VERSION 5.8 ;
BUSBITCHARS "[]" ;
DIVIDERCHAR "/" ;
UNITS
    DATABASE MICRONS 1000 ;
END UNITS

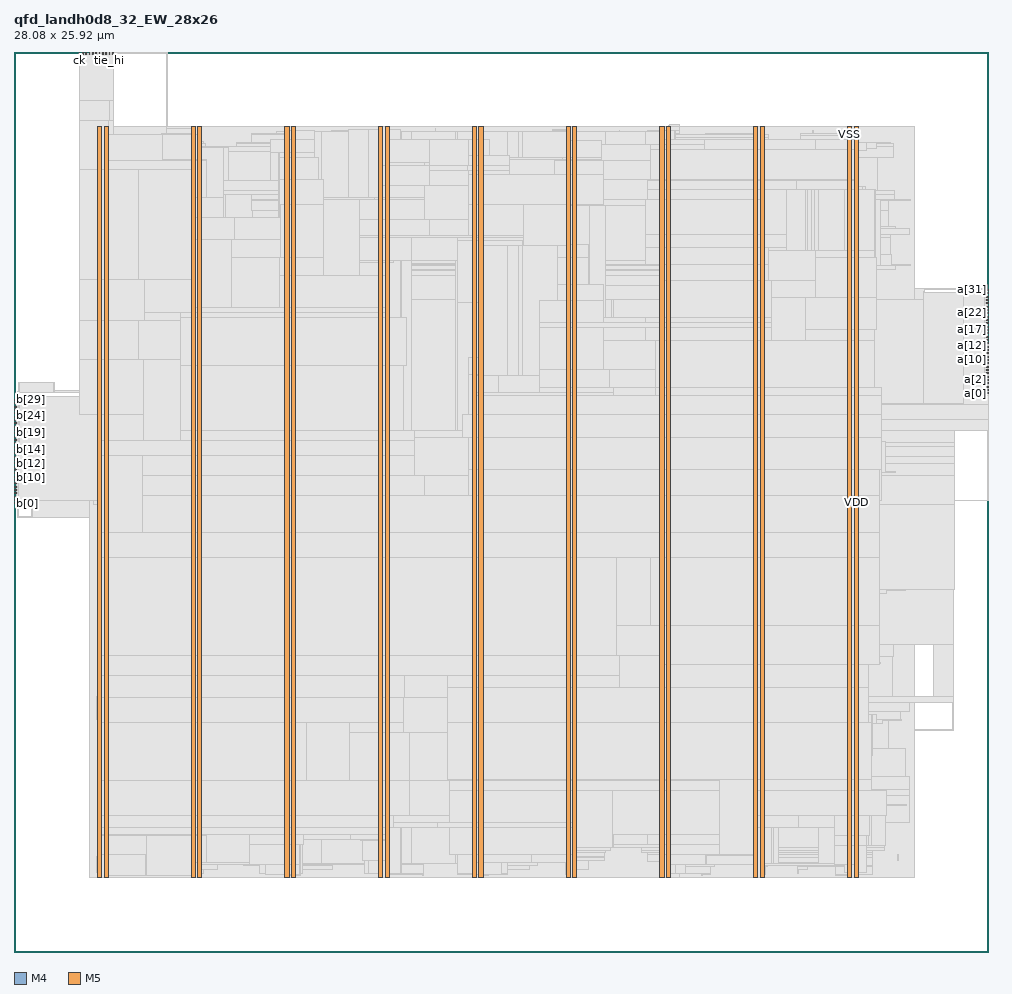
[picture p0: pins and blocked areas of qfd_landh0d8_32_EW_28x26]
MACRO qfd_landh0d8_32_EW_28x26
  FOREIGN qfd_landh0d8_32_EW_28x26 0 0 ;
  CLASS BLOCK ;
  SIZE 28.08 BY 25.92 ;
  PIN a[0]
    DIRECTION INPUT ;
    USE SIGNAL ;
    PORT
      LAYER M4 ;
        RECT  27.996 16.08 28.08 16.104 ;
    END
  END a[0]
  PIN a[10]
    DIRECTION INPUT ;
    USE SIGNAL ;
    PORT
      LAYER M4 ;
        RECT  27.996 17.04 28.08 17.064 ;
    END
  END a[10]
  PIN a[11]
    DIRECTION INPUT ;
    USE SIGNAL ;
    PORT
      LAYER M4 ;
        RECT  27.996 17.136 28.08 17.16 ;
    END
  END a[11]
  PIN a[12]
    DIRECTION INPUT ;
    USE SIGNAL ;
    PORT
      LAYER M4 ;
        RECT  27.996 17.232 28.08 17.256 ;
    END
  END a[12]
  PIN a[13]
    DIRECTION INPUT ;
    USE SIGNAL ;
    PORT
      LAYER M4 ;
        RECT  27.996 17.328 28.08 17.352 ;
    END
  END a[13]
  PIN a[14]
    DIRECTION INPUT ;
    USE SIGNAL ;
    PORT
      LAYER M4 ;
        RECT  27.996 17.424 28.08 17.448 ;
    END
  END a[14]
  PIN a[15]
    DIRECTION INPUT ;
    USE SIGNAL ;
    PORT
      LAYER M4 ;
        RECT  27.996 17.52 28.08 17.544 ;
    END
  END a[15]
  PIN a[16]
    DIRECTION INPUT ;
    USE SIGNAL ;
    PORT
      LAYER M4 ;
        RECT  27.996 17.616 28.08 17.64 ;
    END
  END a[16]
  PIN a[17]
    DIRECTION INPUT ;
    USE SIGNAL ;
    PORT
      LAYER M4 ;
        RECT  27.996 17.712 28.08 17.736 ;
    END
  END a[17]
  PIN a[18]
    DIRECTION INPUT ;
    USE SIGNAL ;
    PORT
      LAYER M4 ;
        RECT  27.996 17.808 28.08 17.832 ;
    END
  END a[18]
  PIN a[19]
    DIRECTION INPUT ;
    USE SIGNAL ;
    PORT
      LAYER M4 ;
        RECT  27.996 17.904 28.08 17.928 ;
    END
  END a[19]
  PIN a[1]
    DIRECTION INPUT ;
    USE SIGNAL ;
    PORT
      LAYER M4 ;
        RECT  27.996 16.176 28.08 16.2 ;
    END
  END a[1]
  PIN a[20]
    DIRECTION INPUT ;
    USE SIGNAL ;
    PORT
      LAYER M4 ;
        RECT  27.996 18 28.08 18.024 ;
    END
  END a[20]
  PIN a[21]
    DIRECTION INPUT ;
    USE SIGNAL ;
    PORT
      LAYER M4 ;
        RECT  27.996 18.096 28.08 18.12 ;
    END
  END a[21]
  PIN a[22]
    DIRECTION INPUT ;
    USE SIGNAL ;
    PORT
      LAYER M4 ;
        RECT  27.996 18.192 28.08 18.216 ;
    END
  END a[22]
  PIN a[23]
    DIRECTION INPUT ;
    USE SIGNAL ;
    PORT
      LAYER M4 ;
        RECT  27.996 18.288 28.08 18.312 ;
    END
  END a[23]
  PIN a[24]
    DIRECTION INPUT ;
    USE SIGNAL ;
    PORT
      LAYER M4 ;
        RECT  27.996 18.384 28.08 18.408 ;
    END
  END a[24]
  PIN a[25]
    DIRECTION INPUT ;
    USE SIGNAL ;
    PORT
      LAYER M4 ;
        RECT  27.996 18.48 28.08 18.504 ;
    END
  END a[25]
  PIN a[26]
    DIRECTION INPUT ;
    USE SIGNAL ;
    PORT
      LAYER M4 ;
        RECT  27.996 18.576 28.08 18.6 ;
    END
  END a[26]
  PIN a[27]
    DIRECTION INPUT ;
    USE SIGNAL ;
    PORT
      LAYER M4 ;
        RECT  27.996 18.672 28.08 18.696 ;
    END
  END a[27]
  PIN a[28]
    DIRECTION INPUT ;
    USE SIGNAL ;
    PORT
      LAYER M4 ;
        RECT  27.996 18.768 28.08 18.792 ;
    END
  END a[28]
  PIN a[29]
    DIRECTION INPUT ;
    USE SIGNAL ;
    PORT
      LAYER M4 ;
        RECT  27.996 18.864 28.08 18.888 ;
    END
  END a[29]
  PIN a[2]
    DIRECTION INPUT ;
    USE SIGNAL ;
    PORT
      LAYER M4 ;
        RECT  27.996 16.272 28.08 16.296 ;
    END
  END a[2]
  PIN a[30]
    DIRECTION INPUT ;
    USE SIGNAL ;
    PORT
      LAYER M4 ;
        RECT  27.996 18.96 28.08 18.984 ;
    END
  END a[30]
  PIN a[31]
    DIRECTION INPUT ;
    USE SIGNAL ;
    PORT
      LAYER M4 ;
        RECT  27.996 19.056 28.08 19.08 ;
    END
  END a[31]
  PIN a[3]
    DIRECTION INPUT ;
    USE SIGNAL ;
    PORT
      LAYER M4 ;
        RECT  27.996 16.368 28.08 16.392 ;
    END
  END a[3]
  PIN a[4]
    DIRECTION INPUT ;
    USE SIGNAL ;
    PORT
      LAYER M4 ;
        RECT  27.996 16.464 28.08 16.488 ;
    END
  END a[4]
  PIN a[5]
    DIRECTION INPUT ;
    USE SIGNAL ;
    PORT
      LAYER M4 ;
        RECT  27.996 16.56 28.08 16.584 ;
    END
  END a[5]
  PIN a[6]
    DIRECTION INPUT ;
    USE SIGNAL ;
    PORT
      LAYER M4 ;
        RECT  27.996 16.656 28.08 16.68 ;
    END
  END a[6]
  PIN a[7]
    DIRECTION INPUT ;
    USE SIGNAL ;
    PORT
      LAYER M4 ;
        RECT  27.996 16.752 28.08 16.776 ;
    END
  END a[7]
  PIN a[8]
    DIRECTION INPUT ;
    USE SIGNAL ;
    PORT
      LAYER M4 ;
        RECT  27.996 16.848 28.08 16.872 ;
    END
  END a[8]
  PIN a[9]
    DIRECTION INPUT ;
    USE SIGNAL ;
    PORT
      LAYER M4 ;
        RECT  27.996 16.944 28.08 16.968 ;
    END
  END a[9]
  PIN b[0]
    DIRECTION OUTPUT ;
    USE SIGNAL ;
    PORT
      LAYER M4 ;
        RECT  0 12.912 0.084 12.936 ;
    END
  END b[0]
  PIN b[10]
    DIRECTION OUTPUT ;
    USE SIGNAL ;
    PORT
      LAYER M4 ;
        RECT  0 13.872 0.084 13.896 ;
    END
  END b[10]
  PIN b[11]
    DIRECTION OUTPUT ;
    USE SIGNAL ;
    PORT
      LAYER M4 ;
        RECT  0 13.968 0.084 13.992 ;
    END
  END b[11]
  PIN b[12]
    DIRECTION OUTPUT ;
    USE SIGNAL ;
    PORT
      LAYER M4 ;
        RECT  0 14.064 0.084 14.088 ;
    END
  END b[12]
  PIN b[13]
    DIRECTION OUTPUT ;
    USE SIGNAL ;
    PORT
      LAYER M4 ;
        RECT  0 14.16 0.084 14.184 ;
    END
  END b[13]
  PIN b[14]
    DIRECTION OUTPUT ;
    USE SIGNAL ;
    PORT
      LAYER M4 ;
        RECT  0 14.256 0.084 14.28 ;
    END
  END b[14]
  PIN b[15]
    DIRECTION OUTPUT ;
    USE SIGNAL ;
    PORT
      LAYER M4 ;
        RECT  0 14.352 0.084 14.376 ;
    END
  END b[15]
  PIN b[16]
    DIRECTION OUTPUT ;
    USE SIGNAL ;
    PORT
      LAYER M4 ;
        RECT  0 14.448 0.084 14.472 ;
    END
  END b[16]
  PIN b[17]
    DIRECTION OUTPUT ;
    USE SIGNAL ;
    PORT
      LAYER M4 ;
        RECT  0 14.544 0.084 14.568 ;
    END
  END b[17]
  PIN b[18]
    DIRECTION OUTPUT ;
    USE SIGNAL ;
    PORT
      LAYER M4 ;
        RECT  0 14.64 0.084 14.664 ;
    END
  END b[18]
  PIN b[19]
    DIRECTION OUTPUT ;
    USE SIGNAL ;
    PORT
      LAYER M4 ;
        RECT  0 14.736 0.084 14.76 ;
    END
  END b[19]
  PIN b[1]
    DIRECTION OUTPUT ;
    USE SIGNAL ;
    PORT
      LAYER M4 ;
        RECT  0 13.008 0.084 13.032 ;
    END
  END b[1]
  PIN b[20]
    DIRECTION OUTPUT ;
    USE SIGNAL ;
    PORT
      LAYER M4 ;
        RECT  0 14.832 0.084 14.856 ;
    END
  END b[20]
  PIN b[21]
    DIRECTION OUTPUT ;
    USE SIGNAL ;
    PORT
      LAYER M4 ;
        RECT  0 14.928 0.084 14.952 ;
    END
  END b[21]
  PIN b[22]
    DIRECTION OUTPUT ;
    USE SIGNAL ;
    PORT
      LAYER M4 ;
        RECT  0 15.024 0.084 15.048 ;
    END
  END b[22]
  PIN b[23]
    DIRECTION OUTPUT ;
    USE SIGNAL ;
    PORT
      LAYER M4 ;
        RECT  0 15.12 0.084 15.144 ;
    END
  END b[23]
  PIN b[24]
    DIRECTION OUTPUT ;
    USE SIGNAL ;
    PORT
      LAYER M4 ;
        RECT  0 15.216 0.084 15.24 ;
    END
  END b[24]
  PIN b[25]
    DIRECTION OUTPUT ;
    USE SIGNAL ;
    PORT
      LAYER M4 ;
        RECT  0 15.312 0.084 15.336 ;
    END
  END b[25]
  PIN b[26]
    DIRECTION OUTPUT ;
    USE SIGNAL ;
    PORT
      LAYER M4 ;
        RECT  0 15.408 0.084 15.432 ;
    END
  END b[26]
  PIN b[27]
    DIRECTION OUTPUT ;
    USE SIGNAL ;
    PORT
      LAYER M4 ;
        RECT  0 15.504 0.084 15.528 ;
    END
  END b[27]
  PIN b[28]
    DIRECTION OUTPUT ;
    USE SIGNAL ;
    PORT
      LAYER M4 ;
        RECT  0 15.6 0.084 15.624 ;
    END
  END b[28]
  PIN b[29]
    DIRECTION OUTPUT ;
    USE SIGNAL ;
    PORT
      LAYER M4 ;
        RECT  0 15.696 0.084 15.72 ;
    END
  END b[29]
  PIN b[2]
    DIRECTION OUTPUT ;
    USE SIGNAL ;
    PORT
      LAYER M4 ;
        RECT  0 13.104 0.084 13.128 ;
    END
  END b[2]
  PIN b[30]
    DIRECTION OUTPUT ;
    USE SIGNAL ;
    PORT
      LAYER M4 ;
        RECT  0 15.792 0.084 15.816 ;
    END
  END b[30]
  PIN b[31]
    DIRECTION OUTPUT ;
    USE SIGNAL ;
    PORT
      LAYER M4 ;
        RECT  0 15.888 0.084 15.912 ;
    END
  END b[31]
  PIN b[3]
    DIRECTION OUTPUT ;
    USE SIGNAL ;
    PORT
      LAYER M4 ;
        RECT  0 13.2 0.084 13.224 ;
    END
  END b[3]
  PIN b[4]
    DIRECTION OUTPUT ;
    USE SIGNAL ;
    PORT
      LAYER M4 ;
        RECT  0 13.296 0.084 13.32 ;
    END
  END b[4]
  PIN b[5]
    DIRECTION OUTPUT ;
    USE SIGNAL ;
    PORT
      LAYER M4 ;
        RECT  0 13.392 0.084 13.416 ;
    END
  END b[5]
  PIN b[6]
    DIRECTION OUTPUT ;
    USE SIGNAL ;
    PORT
      LAYER M4 ;
        RECT  0 13.488 0.084 13.512 ;
    END
  END b[6]
  PIN b[7]
    DIRECTION OUTPUT ;
    USE SIGNAL ;
    PORT
      LAYER M4 ;
        RECT  0 13.584 0.084 13.608 ;
    END
  END b[7]
  PIN b[8]
    DIRECTION OUTPUT ;
    USE SIGNAL ;
    PORT
      LAYER M4 ;
        RECT  0 13.68 0.084 13.704 ;
    END
  END b[8]
  PIN b[9]
    DIRECTION OUTPUT ;
    USE SIGNAL ;
    PORT
      LAYER M4 ;
        RECT  0 13.776 0.084 13.8 ;
    END
  END b[9]
  PIN ck
    DIRECTION INPUT ;
    USE SIGNAL ;
    PORT
      LAYER M5 ;
        RECT  1.872 25.836 1.896 25.92 ;
    END
  END ck
  PIN ck_s
    DIRECTION INPUT ;
    USE SIGNAL ;
    PORT
      LAYER M5 ;
        RECT  1.968 25.836 1.992 25.92 ;
    END
  END ck_s
  PIN en
    DIRECTION INPUT ;
    USE SIGNAL ;
    PORT
      LAYER M5 ;
        RECT  2.064 25.836 2.088 25.92 ;
    END
  END en
  PIN fault
    DIRECTION OUTPUT ;
    USE SIGNAL ;
    PORT
      LAYER M5 ;
        RECT  2.16 25.836 2.184 25.92 ;
    END
  END fault
  PIN k0
    DIRECTION INPUT ;
    USE SIGNAL ;
    PORT
      LAYER M5 ;
        RECT  2.256 25.836 2.28 25.92 ;
    END
  END k0
  PIN k1
    DIRECTION INPUT ;
    USE SIGNAL ;
    PORT
      LAYER M5 ;
        RECT  2.352 25.836 2.376 25.92 ;
    END
  END k1
  PIN k2
    DIRECTION INPUT ;
    USE SIGNAL ;
    PORT
      LAYER M5 ;
        RECT  2.448 25.836 2.472 25.92 ;
    END
  END k2
  PIN k3
    DIRECTION INPUT ;
    USE SIGNAL ;
    PORT
      LAYER M5 ;
        RECT  2.544 25.836 2.568 25.92 ;
    END
  END k3
  PIN rs
    DIRECTION INPUT ;
    USE SIGNAL ;
    PORT
      LAYER M5 ;
        RECT  2.64 25.836 2.664 25.92 ;
    END
  END rs
  PIN tie_hi
    DIRECTION OUTPUT ;
    USE SIGNAL ;
    PORT
      LAYER M5 ;
        RECT  2.736 25.836 2.76 25.92 ;
    END
  END tie_hi
  PIN tie_lo
    DIRECTION OUTPUT ;
    USE SIGNAL ;
    PORT
      LAYER M5 ;
        RECT  2.832 25.836 2.856 25.92 ;
    END
  END tie_lo
  PIN VDD
    DIRECTION INOUT ;
    USE POWER ;
    PORT
      LAYER M5 ;
        RECT  24.192 2.151 24.312 23.769 ;
        RECT  21.492 2.151 21.612 23.769 ;
        RECT  18.792 2.151 18.912 23.769 ;
        RECT  16.092 2.151 16.212 23.769 ;
        RECT  13.392 2.151 13.512 23.769 ;
        RECT  10.692 2.151 10.812 23.769 ;
        RECT  7.992 2.151 8.112 23.769 ;
        RECT  5.292 2.151 5.412 23.769 ;
        RECT  2.592 2.151 2.712 23.769 ;
    END
  END VDD
  PIN VSS
    DIRECTION INOUT ;
    USE GROUND ;
    PORT
      LAYER M5 ;
        RECT  24 2.137 24.12 23.783 ;
        RECT  21.3 2.137 21.42 23.783 ;
        RECT  18.6 2.137 18.72 23.783 ;
        RECT  15.9 2.137 16.02 23.783 ;
        RECT  13.2 2.137 13.32 23.783 ;
        RECT  10.5 2.137 10.62 23.783 ;
        RECT  7.8 2.137 7.92 23.783 ;
        RECT  5.1 2.137 5.22 23.783 ;
        RECT  2.4 2.137 2.52 23.783 ;
    END
  END VSS
  # OT_OBS_CLOSED layer=M5 d_um=1.536 added=76
  OBS
    LAYER RVTN ;
     RECT  2.16 2.16 25.92 2.295 ;
     RECT  2.16 2.565 25.92 2.835 ;
     RECT  2.16 3.105 25.92 3.375 ;
     RECT  2.16 3.645 25.92 3.915 ;
     RECT  2.16 4.185 25.92 4.455 ;
     RECT  2.16 4.725 25.92 4.995 ;
     RECT  2.16 5.265 25.92 5.535 ;
     RECT  2.16 5.805 25.92 6.075 ;
     RECT  2.16 6.345 25.92 6.615 ;
     RECT  2.16 6.885 25.92 7.155 ;
     RECT  2.16 7.425 25.92 7.695 ;
     RECT  2.16 7.965 25.92 8.235 ;
     RECT  2.16 8.505 25.92 8.775 ;
     RECT  2.16 9.045 25.92 9.315 ;
     RECT  2.16 9.585 25.92 9.855 ;
     RECT  2.16 10.125 25.92 10.395 ;
     RECT  2.16 10.665 25.92 10.935 ;
     RECT  2.16 11.205 25.92 11.475 ;
     RECT  2.16 11.745 25.92 12.015 ;
     RECT  2.16 12.285 25.92 12.555 ;
     RECT  2.16 12.825 25.92 13.095 ;
     RECT  2.16 13.365 25.92 13.635 ;
     RECT  2.16 13.905 25.92 14.175 ;
     RECT  2.16 14.445 25.92 14.715 ;
     RECT  2.16 14.985 25.92 15.255 ;
     RECT  2.16 15.525 25.92 15.795 ;
     RECT  2.16 16.065 25.92 16.335 ;
     RECT  2.16 16.605 25.92 16.875 ;
     RECT  2.16 17.145 25.92 17.415 ;
     RECT  2.16 17.685 25.92 17.955 ;
     RECT  2.16 18.225 25.92 18.495 ;
     RECT  2.16 18.765 25.92 19.035 ;
     RECT  2.16 19.305 25.92 19.575 ;
     RECT  2.16 19.845 25.92 20.115 ;
     RECT  2.16 20.385 25.92 20.655 ;
     RECT  2.16 20.925 25.92 21.195 ;
     RECT  2.16 21.465 25.92 21.735 ;
     RECT  2.16 22.005 25.92 22.275 ;
     RECT  2.16 22.545 25.92 22.815 ;
     RECT  2.16 23.085 25.92 23.355 ;
     RECT  2.16 23.625 25.92 23.76 ;
    LAYER RVTP ;
     RECT  2.16 2.295 25.92 2.565 ;
     RECT  2.16 2.835 25.92 3.105 ;
     RECT  2.16 3.375 25.92 3.645 ;
     RECT  2.16 3.915 25.92 4.185 ;
     RECT  2.16 4.455 25.92 4.725 ;
     RECT  2.16 4.995 25.92 5.265 ;
     RECT  2.16 5.535 25.92 5.805 ;
     RECT  2.16 6.075 25.92 6.345 ;
     RECT  2.16 6.615 25.92 6.885 ;
     RECT  2.16 7.155 25.92 7.425 ;
     RECT  2.16 7.695 25.92 7.965 ;
     RECT  2.16 8.235 25.92 8.505 ;
     RECT  2.16 8.775 25.92 9.045 ;
     RECT  2.16 9.315 25.92 9.585 ;
     RECT  2.16 9.855 25.92 10.125 ;
     RECT  2.16 10.395 25.92 10.665 ;
     RECT  2.16 10.935 25.92 11.205 ;
     RECT  2.16 11.475 25.92 11.745 ;
     RECT  2.16 12.015 25.92 12.285 ;
     RECT  2.16 12.555 25.92 12.825 ;
     RECT  2.16 13.095 25.92 13.365 ;
     RECT  2.16 13.635 25.92 13.905 ;
     RECT  2.16 14.175 25.92 14.445 ;
     RECT  2.16 14.715 25.92 14.985 ;
     RECT  2.16 15.255 25.92 15.525 ;
     RECT  2.16 15.795 25.92 16.065 ;
     RECT  2.16 16.335 25.92 16.605 ;
     RECT  2.16 16.875 25.92 17.145 ;
     RECT  2.16 17.415 25.92 17.685 ;
     RECT  2.16 17.955 25.92 18.225 ;
     RECT  2.16 18.495 25.92 18.765 ;
     RECT  2.16 19.035 25.92 19.305 ;
     RECT  2.16 19.575 25.92 19.845 ;
     RECT  2.16 20.115 25.92 20.385 ;
     RECT  2.16 20.655 25.92 20.925 ;
     RECT  2.16 21.195 25.92 21.465 ;
     RECT  2.16 21.735 25.92 22.005 ;
     RECT  2.16 22.275 25.92 22.545 ;
     RECT  2.16 22.815 25.92 23.085 ;
     RECT  2.16 23.355 25.92 23.625 ;
    LAYER M1 ;
     RECT  2.16 2.151 25.92 23.769 ;
    LAYER M2 ;
     RECT  0.103 16.11 0.139 16.128 ;
     RECT  0.103 14.652 0.347 15.012 ;
     RECT  0.103 12.528 0.499 12.546 ;
     RECT  0.499 12.528 0.535 13.086 ;
     RECT  0.139 16.11 1.175 16.398 ;
     RECT  0.535 12.528 2.16 13.662 ;
     RECT  1.175 16.11 2.16 16.164 ;
     RECT  2.16 2.151 18.859 23.769 ;
     RECT  18.859 2.151 19.175 23.814 ;
     RECT  19.175 2.151 25.92 23.769 ;
     RECT  25.92 9.36 25.943 9.378 ;
     RECT  25.92 12.528 25.979 13.428 ;
     RECT  25.92 15.03 26.231 19.098 ;
     RECT  25.92 7.2 26.519 7.218 ;
     RECT  25.979 12.996 26.555 13.428 ;
     RECT  26.231 15.03 26.771 18.288 ;
     RECT  25.92 6.39 27.059 6.408 ;
     RECT  25.92 10.44 27.095 10.458 ;
     RECT  26.771 16.11 27.383 18.288 ;
     RECT  26.771 15.03 27.419 15.318 ;
     RECT  27.383 16.11 27.455 16.398 ;
     RECT  27.383 17.226 27.455 17.514 ;
     RECT  27.419 15.03 27.491 15.048 ;
     RECT  27.455 16.38 27.527 16.398 ;
     RECT  27.383 18.27 27.527 18.288 ;
     RECT  26.231 19.08 27.995 19.098 ;
     RECT  26.555 12.996 28.067 13.014 ;
     RECT  27.455 17.496 28.067 17.514 ;
    LAYER M3 ;
     RECT  2.415 2.143 2.505 2.191 ;
     RECT  7.815 2.143 7.905 2.191 ;
     RECT  13.215 2.143 13.305 2.191 ;
     RECT  24.015 2.143 24.105 2.191 ;
     RECT  5.115 2.143 5.205 2.203 ;
     RECT  10.515 2.143 10.605 2.227 ;
     RECT  11.772 2.191 11.79 2.227 ;
     RECT  13.215 2.191 13.662 2.227 ;
     RECT  15.915 2.143 16.005 2.227 ;
     RECT  18.615 2.143 18.705 2.227 ;
     RECT  19.8 2.191 19.818 2.227 ;
     RECT  21.315 2.143 21.405 2.227 ;
     RECT  23.652 2.191 24.105 2.227 ;
     RECT  7.815 2.191 8.082 2.251 ;
     RECT  10.515 2.227 11.79 2.251 ;
     RECT  18.615 2.227 18.846 2.251 ;
     RECT  19.8 2.227 20.07 2.251 ;
     RECT  5.004 2.203 5.205 2.263 ;
     RECT  2.415 2.191 2.934 2.299 ;
     RECT  2.376 2.299 2.934 2.371 ;
     RECT  5.004 2.263 5.454 2.371 ;
     RECT  7.092 2.251 8.298 2.371 ;
     RECT  12.78 2.227 14.202 2.371 ;
     RECT  15.876 2.227 16.005 2.371 ;
     RECT  22.572 2.263 22.59 2.371 ;
     RECT  2.376 2.371 3.762 2.461 ;
     RECT  18.615 2.251 20.07 2.461 ;
     RECT  21.315 2.227 21.654 2.461 ;
     RECT  22.572 2.371 22.842 2.461 ;
     RECT  23.652 2.227 24.714 2.461 ;
     RECT  7.092 2.371 9.162 2.497 ;
     RECT  12.78 2.371 14.85 2.497 ;
     RECT  21.315 2.461 21.69 2.497 ;
     RECT  22.572 2.461 24.714 2.497 ;
     RECT  2.376 2.461 4.122 2.533 ;
     RECT  5.004 2.371 5.85 2.533 ;
     RECT  6.624 2.497 9.162 2.533 ;
     RECT  10.116 2.251 11.79 2.533 ;
     RECT  12.78 2.497 15.066 2.569 ;
     RECT  2.376 2.533 11.79 2.587 ;
     RECT  12.78 2.569 15.138 2.587 ;
     RECT  18.615 2.461 20.178 2.605 ;
     RECT  15.876 2.371 16.542 2.641 ;
     RECT  2.376 2.587 15.138 2.731 ;
     RECT  15.876 2.641 17.01 2.731 ;
     RECT  21.315 2.497 24.714 2.731 ;
     RECT  2.376 2.731 17.01 2.759 ;
     RECT  25.452 2.641 25.47 2.795 ;
     RECT  18.252 2.605 20.502 2.803 ;
     RECT  21.276 2.731 24.714 2.803 ;
     RECT  2.415 2.759 17.01 2.875 ;
     RECT  18.252 2.803 24.714 2.875 ;
     RECT  2.415 2.875 17.046 2.911 ;
     RECT  18.072 2.875 24.714 2.911 ;
     RECT  2.415 2.911 17.19 3.001 ;
     RECT  18.072 2.911 25.074 3.001 ;
     RECT  2.415 3.001 25.074 3.721 ;
     RECT  2.415 3.721 25.794 4.495 ;
     RECT  2.412 4.495 25.794 4.685 ;
     RECT  2.415 4.685 25.794 5.063 ;
     RECT  2.415 5.063 25.686 5.873 ;
     RECT  2.415 5.873 25.182 6.667 ;
     RECT  2.415 6.667 25.542 6.691 ;
     RECT  2.376 6.691 25.542 6.925 ;
     RECT  2.376 6.925 25.794 7.195 ;
     RECT  27.036 6.385 27.054 7.195 ;
     RECT  2.376 7.195 27.054 7.349 ;
     RECT  2.415 7.349 25.29 8.509 ;
     RECT  2.415 8.509 25.326 8.851 ;
     RECT  26.496 7.349 27.054 8.851 ;
     RECT  2.415 8.851 27.054 10.435 ;
     RECT  0.108 12.523 0.126 12.829 ;
     RECT  2.415 10.435 27.09 12.893 ;
     RECT  2.415 12.893 15.102 12.901 ;
     RECT  0.108 12.829 0.558 12.941 ;
     RECT  2.304 12.901 15.102 13.037 ;
     RECT  0.144 12.941 0.558 13.325 ;
     RECT  2.415 13.037 15.102 13.325 ;
     RECT  0.504 13.325 0.558 13.517 ;
     RECT  0.54 13.517 0.558 13.709 ;
     RECT  15.84 12.893 27.09 13.711 ;
     RECT  2.415 13.325 14.598 13.801 ;
     RECT  2.304 13.801 14.598 14.059 ;
     RECT  2.268 14.059 14.598 14.071 ;
     RECT  15.336 13.711 27.09 14.071 ;
     RECT  2.268 14.071 27.09 14.279 ;
     RECT  0.144 14.347 0.162 14.539 ;
     RECT  2.304 14.279 27.09 14.549 ;
     RECT  0.144 14.539 0.234 14.635 ;
     RECT  0.108 14.635 0.234 14.647 ;
     RECT  2.415 14.549 27.09 14.675 ;
     RECT  12.492 14.675 27.09 15.025 ;
     RECT  28.044 12.991 28.062 15.025 ;
     RECT  0.108 14.647 0.342 15.053 ;
     RECT  2.415 14.675 11.718 15.251 ;
     RECT  12.492 15.025 28.062 15.341 ;
     RECT  2.415 15.251 5.778 15.449 ;
     RECT  2.415 15.449 5.526 15.595 ;
     RECT  2.304 15.595 5.526 15.691 ;
     RECT  6.696 15.251 11.718 15.691 ;
     RECT  12.492 15.341 16.902 15.691 ;
     RECT  17.64 15.341 28.062 15.755 ;
     RECT  2.268 15.691 5.526 15.827 ;
     RECT  2.304 15.827 5.526 15.899 ;
     RECT  0.108 15.053 0.198 15.917 ;
     RECT  6.696 15.691 16.902 15.979 ;
     RECT  17.892 15.755 28.062 16.025 ;
     RECT  6.408 15.979 16.902 16.061 ;
     RECT  0.108 15.917 0.162 16.133 ;
     RECT  2.415 15.899 5.526 16.219 ;
     RECT  6.408 16.061 13.698 16.219 ;
     RECT  14.508 16.061 16.902 16.375 ;
     RECT  0.144 16.133 0.162 16.403 ;
     RECT  1.152 16.141 1.17 16.403 ;
     RECT  14.508 16.375 17.01 16.573 ;
     RECT  14.508 16.573 17.154 16.609 ;
     RECT  2.415 16.219 13.698 16.807 ;
     RECT  14.508 16.609 17.19 16.807 ;
     RECT  2.415 16.807 17.19 16.891 ;
     RECT  17.928 16.025 28.062 16.891 ;
     RECT  2.415 16.891 28.062 17.069 ;
     RECT  2.415 17.069 5.49 17.165 ;
     RECT  6.264 17.069 28.062 17.249 ;
     RECT  6.3 17.249 28.062 17.519 ;
     RECT  6.3 17.519 27.99 17.549 ;
     RECT  6.3 17.549 27.522 17.837 ;
     RECT  2.415 17.165 5.418 18.031 ;
     RECT  6.3 17.837 26.55 18.031 ;
     RECT  2.415 18.031 26.55 18.149 ;
     RECT  27.288 17.837 27.522 18.293 ;
     RECT  15.66 18.149 26.55 18.317 ;
     RECT  15.66 18.317 24.93 18.419 ;
     RECT  25.704 18.317 26.55 18.419 ;
     RECT  15.66 18.419 24.786 18.464 ;
     RECT  15.66 18.464 24.678 18.478 ;
     RECT  26.208 18.419 26.55 18.509 ;
     RECT  2.415 18.149 14.886 18.571 ;
     RECT  27.36 18.293 27.486 18.605 ;
     RECT  2.376 18.571 14.886 18.749 ;
     RECT  2.376 18.749 14.31 18.797 ;
     RECT  27.396 18.605 27.486 18.893 ;
     RECT  26.208 18.509 26.226 19.031 ;
     RECT  27.972 19.051 27.99 19.103 ;
     RECT  15.66 18.478 21.726 19.201 ;
     RECT  2.415 18.797 14.31 19.471 ;
     RECT  15.12 19.201 21.726 19.471 ;
     RECT  22.824 18.478 24.678 19.579 ;
     RECT  2.415 19.471 21.726 19.615 ;
     RECT  22.644 19.579 24.678 19.615 ;
     RECT  2.415 19.615 24.678 19.651 ;
     RECT  2.415 19.651 25.398 19.771 ;
     RECT  2.415 19.771 25.794 19.777 ;
     RECT  2.196 19.777 25.794 19.811 ;
     RECT  2.196 19.811 25.254 20.573 ;
     RECT  6.876 20.573 25.254 20.659 ;
     RECT  6.876 20.659 25.794 20.849 ;
     RECT  6.876 20.849 25.398 20.885 ;
     RECT  6.876 20.885 25.182 21.361 ;
     RECT  6.84 21.361 25.182 21.631 ;
     RECT  6.84 21.631 25.794 21.677 ;
     RECT  2.196 20.573 6.102 21.811 ;
     RECT  6.84 21.677 25.362 21.811 ;
     RECT  2.196 21.811 25.362 21.929 ;
     RECT  2.196 21.929 24.858 22.891 ;
     RECT  2.196 22.891 25.326 23.189 ;
     RECT  2.196 23.189 5.526 23.279 ;
     RECT  6.408 23.189 25.326 23.279 ;
     RECT  6.408 23.279 21.798 23.315 ;
     RECT  22.536 23.279 25.218 23.315 ;
     RECT  3.996 23.279 5.454 23.351 ;
     RECT  22.536 23.315 24.297 23.351 ;
     RECT  9.144 23.315 21.726 23.459 ;
     RECT  3.996 23.351 5.397 23.507 ;
     RECT  22.644 23.351 24.297 23.507 ;
     RECT  3.996 23.507 5.274 23.549 ;
     RECT  6.84 23.315 8.37 23.549 ;
     RECT  9.144 23.459 11.286 23.549 ;
     RECT  12.132 23.459 21.726 23.549 ;
     RECT  4.248 23.549 5.274 23.585 ;
     RECT  6.84 23.549 7.905 23.585 ;
     RECT  12.132 23.549 14.094 23.585 ;
     RECT  15.516 23.549 19.17 23.585 ;
     RECT  19.908 23.549 21.405 23.585 ;
     RECT  22.644 23.507 24.105 23.585 ;
     RECT  7.56 23.585 7.905 23.621 ;
     RECT  12.132 23.585 13.305 23.621 ;
     RECT  23.94 23.585 24.105 23.621 ;
     RECT  17.424 23.585 17.442 23.645 ;
     RECT  18.252 23.585 19.17 23.645 ;
     RECT  9.144 23.549 9.666 23.657 ;
     RECT  15.516 23.585 16.074 23.657 ;
     RECT  23.004 23.585 23.022 23.657 ;
     RECT  9.648 23.657 9.666 23.693 ;
     RECT  15.516 23.657 16.005 23.693 ;
     RECT  10.515 23.549 11.106 23.699 ;
     RECT  4.392 23.585 5.274 23.729 ;
     RECT  12.132 23.621 12.15 23.729 ;
     RECT  4.392 23.729 5.205 23.777 ;
     RECT  7.815 23.621 7.905 23.777 ;
     RECT  10.515 23.699 10.605 23.777 ;
     RECT  13.215 23.621 13.305 23.777 ;
     RECT  15.915 23.693 16.005 23.777 ;
     RECT  18.615 23.645 19.17 23.777 ;
     RECT  21.315 23.585 21.405 23.777 ;
     RECT  24.015 23.621 24.105 23.777 ;
     RECT  18.864 23.777 19.17 23.819 ;
     RECT  2.196 23.279 2.826 24.557 ;
     RECT  2.196 24.557 2.214 24.653 ;
     RECT  2.196 25.771 2.214 25.901 ;
     RECT  4.392 23.777 4.41 25.901 ;
    LAYER M4 ;
     RECT  0.084 12.912 0.133 12.936 ;
     RECT  0.06 12.936 0.133 13.008 ;
     RECT  0.084 13.008 0.133 13.032 ;
     RECT  0.06 13.032 0.133 13.104 ;
     RECT  0.084 13.104 0.133 13.128 ;
     RECT  0.06 13.128 0.133 13.2 ;
     RECT  0.084 13.2 0.133 13.224 ;
     RECT  0.06 13.224 0.133 13.296 ;
     RECT  0.084 13.296 0.133 13.32 ;
     RECT  0.06 13.32 0.133 13.392 ;
     RECT  0.084 13.392 0.133 13.416 ;
     RECT  0.06 13.416 0.133 13.488 ;
     RECT  0.084 13.488 0.133 13.512 ;
     RECT  0.06 13.512 0.133 13.584 ;
     RECT  0.084 13.584 0.133 13.608 ;
     RECT  0.06 13.608 0.133 13.68 ;
     RECT  0.084 13.68 0.133 13.704 ;
     RECT  0.06 13.704 0.133 13.776 ;
     RECT  0.084 13.776 0.133 13.8 ;
     RECT  0.06 13.8 0.133 13.872 ;
     RECT  0.084 13.872 0.133 13.896 ;
     RECT  0.06 13.896 0.133 13.968 ;
     RECT  0.084 13.968 0.133 13.992 ;
     RECT  0.06 13.992 0.133 14.064 ;
     RECT  0.084 14.064 0.133 14.088 ;
     RECT  0.06 14.088 0.133 14.16 ;
     RECT  0.084 14.16 0.133 14.184 ;
     RECT  0.06 14.184 0.133 14.256 ;
     RECT  0.084 14.256 0.133 14.28 ;
     RECT  0.06 14.28 0.133 14.352 ;
     RECT  0.084 14.352 0.133 14.376 ;
     RECT  0.06 14.376 0.133 14.448 ;
     RECT  0.084 14.448 0.133 14.472 ;
     RECT  0.06 14.472 0.133 14.544 ;
     RECT  0.084 14.544 0.133 14.568 ;
     RECT  0.06 14.568 0.133 14.64 ;
     RECT  0.084 14.64 0.133 14.664 ;
     RECT  0.06 14.664 0.133 14.736 ;
     RECT  0.084 14.736 0.133 14.76 ;
     RECT  0.06 14.76 0.133 14.832 ;
     RECT  0.084 14.832 0.133 14.856 ;
     RECT  0.06 14.856 0.133 14.928 ;
     RECT  0.084 14.928 0.133 14.952 ;
     RECT  0.06 14.952 0.133 15.024 ;
     RECT  0.084 15.024 0.133 15.048 ;
     RECT  0.06 15.048 0.133 15.12 ;
     RECT  0.084 15.12 0.133 15.144 ;
     RECT  0.06 15.144 0.133 15.216 ;
     RECT  0.084 15.216 0.133 15.24 ;
     RECT  0.06 15.24 0.133 15.312 ;
     RECT  0.084 15.312 0.133 15.336 ;
     RECT  0.06 15.336 0.133 15.408 ;
     RECT  0.084 15.408 0.133 15.432 ;
     RECT  0.06 15.432 0.133 15.504 ;
     RECT  0.084 15.504 0.133 15.528 ;
     RECT  0.06 15.528 0.133 15.6 ;
     RECT  0.084 15.6 0.133 15.624 ;
     RECT  0.06 15.624 0.133 15.696 ;
     RECT  0.084 15.696 0.133 15.72 ;
     RECT  0.06 15.72 0.133 15.792 ;
     RECT  0.084 15.792 0.133 15.816 ;
     RECT  0.06 15.816 0.133 15.888 ;
     RECT  0.084 15.888 0.133 15.912 ;
     RECT  0.133 12.912 0.137 16.008 ;
     RECT  2.053 23.712 2.185 23.736 ;
     RECT  2.141 25.776 2.185 25.8 ;
     RECT  2.185 23.712 2.213 24.648 ;
     RECT  2.185 25.776 2.225 25.896 ;
     RECT  2.365 2.304 2.408 2.328 ;
     RECT  2.401 4.512 2.408 4.536 ;
     RECT  0.137 13.008 2.408 16.008 ;
     RECT  1.957 21.984 2.408 22.008 ;
     RECT  2.213 23.568 2.408 24.648 ;
     RECT  2.408 2.148 2.512 24.648 ;
     RECT  2.512 2.208 2.675 24.648 ;
     RECT  2.675 2.208 2.704 24.552 ;
     RECT  2.704 23.952 2.812 24.552 ;
     RECT  2.812 24.528 2.867 24.552 ;
     RECT  2.704 4.416 3.413 22.824 ;
     RECT  3.413 20.544 3.449 22.824 ;
     RECT  3.413 4.416 3.779 19.368 ;
     RECT  3.449 21.12 3.917 22.824 ;
     RECT  2.704 2.208 4.165 3.432 ;
     RECT  3.779 4.416 4.165 19.32 ;
     RECT  3.917 22.176 4.22 22.824 ;
     RECT  2.225 25.872 4.421 25.896 ;
     RECT  3.917 21.12 4.957 21.144 ;
     RECT  4.165 2.208 5.108 19.32 ;
     RECT  4.957 20.4 5.108 21.144 ;
     RECT  4.22 22.176 5.108 23.544 ;
     RECT  5.108 2.148 5.212 23.772 ;
     RECT  5.212 2.418 5.404 23.502 ;
     RECT  5.404 2.544 6.035 23.16 ;
     RECT  6.035 2.544 6.149 21.144 ;
     RECT  6.035 22.224 6.185 23.16 ;
     RECT  6.149 19.776 6.275 21.144 ;
     RECT  6.149 2.544 7.081 18.744 ;
     RECT  6.185 22.224 7.381 23.064 ;
     RECT  6.275 19.92 7.621 21.144 ;
     RECT  7.381 22.224 7.621 23.4 ;
     RECT  7.081 2.256 7.669 18.744 ;
     RECT  7.621 19.728 7.669 23.4 ;
     RECT  7.669 2.256 7.808 23.4 ;
     RECT  7.808 2.148 7.912 23.772 ;
     RECT  7.912 2.208 8.243 23.64 ;
     RECT  8.243 2.256 8.309 23.64 ;
     RECT  8.309 2.544 8.867 23.64 ;
     RECT  8.867 4.944 9.637 23.64 ;
     RECT  8.867 2.544 10.105 3.96 ;
     RECT  10.105 2.256 10.213 3.96 ;
     RECT  9.637 4.944 10.213 23.688 ;
     RECT  10.213 2.256 10.508 23.688 ;
     RECT  10.508 2.148 10.612 23.772 ;
     RECT  10.612 2.256 11.117 23.688 ;
     RECT  11.117 2.256 11.153 23.64 ;
     RECT  11.153 2.544 11.441 23.64 ;
     RECT  11.441 2.544 12.716 18.792 ;
     RECT  11.441 19.824 12.716 23.64 ;
     RECT  12.716 2.544 12.769 23.64 ;
     RECT  12.769 2.256 13.208 23.64 ;
     RECT  13.208 2.148 13.312 23.772 ;
     RECT  13.312 2.256 14.213 23.64 ;
     RECT  14.213 2.592 14.531 23.64 ;
     RECT  14.531 9.072 14.645 23.64 ;
     RECT  14.531 2.592 15.908 8.04 ;
     RECT  14.645 9.072 15.908 12.936 ;
     RECT  14.645 13.92 15.908 23.64 ;
     RECT  15.908 2.148 16.012 23.772 ;
     RECT  16.012 2.418 16.204 23.64 ;
     RECT  16.204 5.664 17.021 23.64 ;
     RECT  16.204 3.36 17.18 4.68 ;
     RECT  17.18 3.024 17.221 4.68 ;
     RECT  17.021 5.664 17.221 18.792 ;
     RECT  17.221 3.024 17.267 18.792 ;
     RECT  17.021 19.92 18.181 23.64 ;
     RECT  17.267 3.12 18.608 18.792 ;
     RECT  18.181 19.824 18.608 23.64 ;
     RECT  18.608 2.148 18.712 23.772 ;
     RECT  18.712 2.256 19.043 23.64 ;
     RECT  19.043 2.256 19.325 23.4 ;
     RECT  19.325 2.544 20.045 23.4 ;
     RECT  20.045 2.544 21.308 23.112 ;
     RECT  21.308 2.148 21.412 23.772 ;
     RECT  21.412 2.418 21.604 23.502 ;
     RECT  21.604 2.544 21.827 23.112 ;
     RECT  21.827 2.544 21.881 18.456 ;
     RECT  21.881 8.352 21.971 18.456 ;
     RECT  21.881 2.544 22.025 7.368 ;
     RECT  21.971 8.4 22.789 18.456 ;
     RECT  21.827 19.776 22.789 23.112 ;
     RECT  22.789 8.4 22.849 23.112 ;
     RECT  22.025 3.6 22.957 7.368 ;
     RECT  22.849 8.4 22.957 23.304 ;
     RECT  22.957 3.6 23.065 23.304 ;
     RECT  22.025 2.544 23.173 2.568 ;
     RECT  23.065 3.6 23.173 23.4 ;
     RECT  23.173 2.544 23.929 23.4 ;
     RECT  23.929 2.304 24.008 23.4 ;
     RECT  24.008 2.148 24.112 23.772 ;
     RECT  24.112 2.304 24.304 23.502 ;
     RECT  24.304 12.768 24.437 22.056 ;
     RECT  24.437 13.008 24.509 22.056 ;
     RECT  24.304 2.304 24.545 11.208 ;
     RECT  24.304 23.088 24.545 23.304 ;
     RECT  24.545 3.072 24.611 11.208 ;
     RECT  24.509 13.008 24.689 21.96 ;
     RECT  24.611 3.072 24.7 6.84 ;
     RECT  24.7 5.664 24.725 6.84 ;
     RECT  24.611 8.304 24.761 11.208 ;
     RECT  24.689 19.776 24.803 21.96 ;
     RECT  24.725 6.576 24.833 6.84 ;
     RECT  24.761 8.304 24.833 9.096 ;
     RECT  24.545 23.136 24.833 23.304 ;
     RECT  24.761 10.32 24.851 11.208 ;
     RECT  24.803 19.776 24.941 21.672 ;
     RECT  24.833 8.304 24.947 8.328 ;
     RECT  24.689 13.008 24.977 14.712 ;
     RECT  24.833 6.576 25.013 6.696 ;
     RECT  24.7 3.072 25.085 4.632 ;
     RECT  24.977 13.824 25.085 14.712 ;
     RECT  24.851 10.32 25.121 10.44 ;
     RECT  25.085 3.936 25.139 4.632 ;
     RECT  24.833 23.28 25.229 23.304 ;
     RECT  24.941 19.776 25.265 20.088 ;
     RECT  25.085 13.824 25.373 13.848 ;
     RECT  25.013 6.672 25.553 6.696 ;
     RECT  25.121 10.416 25.661 10.44 ;
     RECT  25.139 4.224 25.697 4.248 ;
     RECT  25.265 19.776 25.805 19.8 ;
     RECT  24.941 21.648 25.805 21.672 ;
     RECT  24.689 15.792 26.197 18.792 ;
     RECT  26.197 15.792 27.353 18.984 ;
     RECT  27.353 16.08 27.961 18.984 ;
     RECT  27.961 16.08 27.996 16.104 ;
     RECT  27.961 16.104 28.044 16.176 ;
     RECT  27.961 16.176 27.996 16.2 ;
     RECT  27.961 16.2 28.044 16.272 ;
     RECT  27.961 16.272 27.996 16.296 ;
     RECT  27.961 16.296 28.044 16.368 ;
     RECT  27.961 16.368 27.996 16.392 ;
     RECT  27.961 16.392 28.044 16.464 ;
     RECT  27.961 16.464 27.996 16.488 ;
     RECT  27.961 16.488 28.044 16.56 ;
     RECT  27.961 16.56 27.996 16.584 ;
     RECT  27.961 16.584 28.044 16.656 ;
     RECT  27.961 16.656 27.996 16.68 ;
     RECT  27.961 16.68 28.044 16.752 ;
     RECT  27.961 16.752 27.996 16.776 ;
     RECT  27.961 16.776 28.044 16.848 ;
     RECT  27.961 16.848 27.996 16.872 ;
     RECT  27.961 16.872 28.044 16.944 ;
     RECT  27.961 16.944 27.996 16.968 ;
     RECT  27.961 16.968 28.044 17.04 ;
     RECT  27.961 17.04 27.996 17.064 ;
     RECT  27.961 17.064 28.044 17.136 ;
     RECT  27.961 17.136 27.996 17.16 ;
     RECT  27.961 17.16 28.044 17.232 ;
     RECT  27.961 17.232 27.996 17.256 ;
     RECT  27.961 17.256 28.044 17.328 ;
     RECT  27.961 17.328 27.996 17.352 ;
     RECT  27.961 17.352 28.044 17.424 ;
     RECT  27.961 17.424 27.996 17.448 ;
     RECT  27.961 17.448 28.044 17.52 ;
     RECT  27.961 17.52 27.996 17.544 ;
     RECT  27.961 17.544 28.044 17.616 ;
     RECT  27.961 17.616 27.996 17.64 ;
     RECT  27.961 17.64 28.044 17.712 ;
     RECT  27.961 17.712 27.996 17.736 ;
     RECT  27.961 17.736 28.044 17.808 ;
     RECT  27.961 17.808 27.996 17.832 ;
     RECT  27.961 17.832 28.044 17.904 ;
     RECT  27.961 17.904 27.996 17.928 ;
     RECT  27.961 17.928 28.044 18 ;
     RECT  27.961 18 27.996 18.024 ;
     RECT  27.961 18.024 28.044 18.096 ;
     RECT  27.961 18.096 27.996 18.12 ;
     RECT  27.961 18.12 28.044 18.192 ;
     RECT  27.961 18.192 27.996 18.216 ;
     RECT  27.961 18.216 28.044 18.288 ;
     RECT  27.961 18.288 27.996 18.312 ;
     RECT  27.961 18.312 28.044 18.384 ;
     RECT  27.961 18.384 27.996 18.408 ;
     RECT  27.961 18.408 28.044 18.48 ;
     RECT  27.961 18.48 27.996 18.504 ;
     RECT  27.961 18.504 28.044 18.576 ;
     RECT  27.961 18.576 27.996 18.6 ;
     RECT  27.961 18.6 28.044 18.672 ;
     RECT  27.961 18.672 27.996 18.696 ;
     RECT  27.961 18.696 28.044 18.768 ;
     RECT  27.961 18.768 27.996 18.792 ;
     RECT  27.961 18.792 28.044 18.864 ;
     RECT  27.961 18.864 27.996 18.888 ;
     RECT  27.961 18.888 28.044 18.96 ;
     RECT  27.961 18.96 27.996 18.984 ;
     RECT  27.961 18.984 28.044 19.056 ;
     RECT  27.961 19.056 27.996 19.08 ;
    LAYER M5 ;
     RECT  2.4 2.137 2.52 2.151 ;
     RECT  5.1 2.137 5.22 2.151 ;
     RECT  7.8 2.137 7.92 2.151 ;
     RECT  10.5 2.137 10.62 2.151 ;
     RECT  13.2 2.137 13.32 2.151 ;
     RECT  15.9 2.137 16.02 2.151 ;
     RECT  18.6 2.137 18.72 2.151 ;
     RECT  21.3 2.137 21.42 2.151 ;
     RECT  24 2.137 24.12 2.151 ;
     RECT  7.8 2.151 8.112 2.197 ;
     RECT  7.8 2.197 8.232 2.245 ;
     RECT  13.2 2.151 13.512 2.245 ;
     RECT  7.248 2.245 8.232 2.533 ;
     RECT  24 2.151 24.312 2.533 ;
     RECT  5.1 2.151 5.412 2.581 ;
     RECT  13.2 2.245 14.04 2.581 ;
     RECT  10.5 2.151 10.812 2.629 ;
     RECT  19.92 2.533 19.944 2.773 ;
     RECT  2.4 2.151 2.712 2.821 ;
     RECT  3.792 2.197 3.816 2.821 ;
     RECT  13.2 2.581 14.904 2.821 ;
     RECT  15.9 2.151 16.212 2.821 ;
     RECT  18.6 2.151 18.912 2.821 ;
     RECT  19.92 2.773 20.184 2.821 ;
     RECT  23.616 2.533 24.312 3.061 ;
     RECT  6.768 2.533 8.232 3.109 ;
     RECT  18.6 2.821 20.328 3.109 ;
     RECT  10.032 2.629 10.812 3.205 ;
     RECT  9.984 3.205 10.812 3.253 ;
     RECT  2.4 2.821 3.816 3.349 ;
     RECT  5.1 2.581 5.544 3.349 ;
     RECT  23.616 3.061 24.552 3.349 ;
     RECT  2.4 3.349 5.544 3.397 ;
     RECT  6.768 3.109 8.328 3.397 ;
     RECT  9.696 3.253 10.812 3.397 ;
     RECT  17.232 3.013 17.256 3.397 ;
     RECT  18.24 3.109 20.328 3.397 ;
     RECT  2.4 3.397 10.812 3.589 ;
     RECT  12.528 2.821 16.212 3.589 ;
     RECT  21.3 2.151 21.612 3.589 ;
     RECT  12.192 3.589 16.212 3.731 ;
     RECT  2.4 3.589 10.92 3.925 ;
     RECT  21.3 3.589 22.584 3.925 ;
     RECT  23.616 3.349 24.648 3.925 ;
     RECT  21.3 3.925 25.128 4.643 ;
     RECT  12.528 3.731 16.212 4.645 ;
     RECT  17.232 3.397 20.328 4.645 ;
     RECT  2.4 3.925 11.4 4.931 ;
     RECT  12.528 4.645 20.328 4.933 ;
     RECT  12.48 4.933 20.328 4.981 ;
     RECT  21.3 4.643 24.696 4.981 ;
     RECT  9.648 4.931 11.4 6.323 ;
     RECT  12.48 4.981 24.696 6.611 ;
     RECT  2.4 4.931 8.424 6.613 ;
     RECT  9.648 6.323 11.208 6.613 ;
     RECT  2.4 6.613 11.208 7.333 ;
     RECT  12.48 6.611 24.6 7.619 ;
     RECT  2.4 7.333 11.256 7.957 ;
     RECT  12.48 7.619 17.448 7.957 ;
     RECT  18.6 7.619 24.6 8.293 ;
     RECT  2.4 7.957 17.448 8.531 ;
     RECT  18.6 8.293 24.936 9.397 ;
     RECT  2.4 8.531 17.352 11.365 ;
     RECT  18.336 9.397 24.936 11.365 ;
     RECT  2.4 11.365 24.936 12.083 ;
     RECT  3.696 12.083 24.936 13.139 ;
     RECT  3.696 13.139 11.832 13.715 ;
     RECT  13.104 13.139 24.936 13.909 ;
     RECT  2.4 12.083 2.712 14.293 ;
     RECT  3.696 13.715 11.544 14.293 ;
     RECT  2.4 14.293 11.544 14.723 ;
     RECT  13.104 13.909 24.984 14.821 ;
     RECT  4.8 14.723 11.544 15.011 ;
     RECT  12.912 14.821 24.984 15.491 ;
     RECT  2.4 14.723 3.72 15.493 ;
     RECT  0.144 14.389 0.168 16.019 ;
     RECT  13.2 15.491 24.984 16.019 ;
     RECT  13.2 16.019 17.256 16.115 ;
     RECT  15.12 16.115 17.256 16.259 ;
     RECT  18.48 16.019 24.984 16.259 ;
     RECT  13.2 16.115 13.944 16.595 ;
     RECT  13.2 16.595 13.512 16.645 ;
     RECT  15.12 16.259 17.16 16.787 ;
     RECT  4.8 15.011 11.208 16.885 ;
     RECT  1.872 15.493 3.72 17.075 ;
     RECT  13.104 16.645 13.512 17.123 ;
     RECT  18.48 16.259 24.792 17.603 ;
     RECT  18.48 17.603 21.816 17.605 ;
     RECT  22.8 17.603 24.792 17.941 ;
     RECT  15.12 16.787 16.968 17.989 ;
     RECT  18.192 17.605 21.816 17.989 ;
     RECT  15.12 17.989 21.816 18.131 ;
     RECT  1.872 17.075 3.576 18.181 ;
     RECT  4.8 16.885 11.304 18.275 ;
     RECT  18.192 18.131 21.816 18.275 ;
     RECT  4.8 18.275 10.812 18.419 ;
     RECT  5.1 18.419 10.812 18.563 ;
     RECT  13.2 17.123 13.512 18.709 ;
     RECT  15.12 18.131 16.968 18.755 ;
     RECT  22.8 17.941 24.84 18.851 ;
     RECT  15.648 18.755 16.968 19.235 ;
     RECT  18.6 18.275 21.816 19.331 ;
     RECT  1.872 18.181 3.768 19.379 ;
     RECT  7.632 18.563 10.812 19.475 ;
     RECT  18.6 19.331 21.72 19.813 ;
     RECT  9.936 19.475 10.812 19.861 ;
     RECT  9.936 19.861 10.92 19.909 ;
     RECT  7.632 19.475 8.904 20.003 ;
     RECT  15.648 19.235 16.536 20.003 ;
     RECT  23.088 18.851 24.84 20.003 ;
     RECT  23.088 20.003 24.792 20.195 ;
     RECT  18.192 19.813 21.72 20.293 ;
     RECT  15.9 20.003 16.536 20.389 ;
     RECT  12.768 18.709 13.512 20.485 ;
     RECT  14.64 20.341 14.664 20.485 ;
     RECT  5.1 18.563 6.264 20.533 ;
     RECT  9.936 19.909 11.448 20.581 ;
     RECT  12.768 20.485 14.664 20.581 ;
     RECT  9.936 20.581 14.664 20.627 ;
     RECT  18.192 20.293 22.248 20.675 ;
     RECT  9.936 20.627 11.976 21.107 ;
     RECT  5.1 20.533 6.36 21.155 ;
     RECT  15.9 20.389 16.584 21.493 ;
     RECT  7.68 20.003 8.904 21.541 ;
     RECT  13.104 20.627 14.664 21.541 ;
     RECT  15.9 21.493 16.968 21.541 ;
     RECT  9.936 21.107 11.832 21.683 ;
     RECT  18.192 20.675 21.612 21.683 ;
     RECT  5.1 21.155 6.024 21.731 ;
     RECT  10.368 21.683 11.832 21.731 ;
     RECT  24 20.195 24.792 21.971 ;
     RECT  18.24 21.683 21.612 21.973 ;
     RECT  10.5 21.731 11.832 22.069 ;
     RECT  18.24 21.973 22.536 22.213 ;
     RECT  24 21.971 24.312 22.213 ;
     RECT  7.632 21.541 8.904 22.259 ;
     RECT  18.24 22.213 24.312 22.259 ;
     RECT  13.104 21.541 16.968 22.403 ;
     RECT  13.104 22.403 14.28 22.501 ;
     RECT  1.872 19.379 3.576 22.547 ;
     RECT  10.5 22.069 11.976 22.643 ;
     RECT  13.056 22.501 14.28 22.643 ;
     RECT  11.808 22.643 11.976 22.739 ;
     RECT  15.552 22.403 16.968 22.787 ;
     RECT  5.1 21.731 5.544 22.789 ;
     RECT  4.272 22.789 5.544 22.835 ;
     RECT  15.552 22.787 16.92 22.835 ;
     RECT  7.632 22.259 8.76 22.883 ;
     RECT  15.792 22.835 16.92 22.883 ;
     RECT  13.104 22.643 14.28 22.931 ;
     RECT  7.632 22.883 8.664 23.029 ;
     RECT  18.336 22.259 24.312 23.123 ;
     RECT  18.336 23.123 19.896 23.267 ;
     RECT  15.9 22.883 16.92 23.363 ;
     RECT  7.392 23.029 8.664 23.411 ;
     RECT  11.952 22.739 11.976 23.411 ;
     RECT  13.104 22.931 13.704 23.411 ;
     RECT  18.6 23.267 19.896 23.411 ;
     RECT  23.088 23.123 24.312 23.411 ;
     RECT  4.272 22.835 5.412 23.555 ;
     RECT  7.8 23.411 8.664 23.651 ;
     RECT  18.6 23.411 19.032 23.651 ;
     RECT  5.1 23.555 5.412 23.769 ;
     RECT  7.8 23.651 8.112 23.769 ;
     RECT  10.5 22.643 10.812 23.769 ;
     RECT  13.2 23.411 13.512 23.769 ;
     RECT  15.9 23.363 16.212 23.769 ;
     RECT  18.6 23.651 18.912 23.769 ;
     RECT  21.3 23.123 21.612 23.769 ;
     RECT  24 23.411 24.312 23.769 ;
     RECT  5.1 23.769 5.22 23.783 ;
     RECT  7.8 23.769 7.92 23.783 ;
     RECT  10.5 23.769 10.62 23.783 ;
     RECT  13.2 23.769 13.32 23.783 ;
     RECT  15.9 23.769 16.02 23.783 ;
     RECT  18.6 23.769 18.72 23.783 ;
     RECT  21.3 23.769 21.42 23.783 ;
     RECT  24 23.769 24.12 23.783 ;
     RECT  1.872 22.547 2.712 23.941 ;
     RECT  1.872 23.941 2.76 24.517 ;
     RECT  1.872 24.517 2.856 25.836 ;
     RECT  1.896 25.836 1.968 25.872 ;
     RECT  1.992 25.836 2.064 25.872 ;
     RECT  2.088 25.836 2.16 25.872 ;
     RECT  2.184 25.836 2.256 25.872 ;
     RECT  2.28 25.836 2.352 25.872 ;
     RECT  2.376 25.836 2.448 25.872 ;
     RECT  2.472 25.836 2.544 25.872 ;
     RECT  2.568 25.836 2.64 25.872 ;
     RECT  2.664 25.836 2.736 25.872 ;
     RECT  2.76 25.836 2.832 25.872 ;
     RECT  2.712 2.197 3.792 2.821 ;
     RECT  3.816 2.197 5.1 3.349 ;
     RECT  5.412 2.533 6.768 2.581 ;
     RECT  18.912 2.533 19.92 2.821 ;
     RECT  19.944 2.533 21.3 2.773 ;
     RECT  5.544 2.581 6.768 3.397 ;
     RECT  14.904 2.581 15.9 2.821 ;
     RECT  20.184 2.773 21.3 2.821 ;
     RECT  20.328 2.821 21.3 4.981 ;
     RECT  16.212 3.013 17.232 4.645 ;
     RECT  17.256 3.013 18.6 3.109 ;
     RECT  17.256 3.109 18.24 3.397 ;
     RECT  8.328 3.253 9.696 3.397 ;
     RECT  10.92 3.589 12.192 3.731 ;
     RECT  22.584 3.589 23.616 3.925 ;
     RECT  10.92 3.731 12.528 3.925 ;
     RECT  11.4 3.925 12.528 4.933 ;
     RECT  8.424 4.931 9.648 6.613 ;
     RECT  11.4 4.933 12.48 6.323 ;
     RECT  11.208 6.323 12.48 7.333 ;
     RECT  11.256 7.333 12.48 7.957 ;
     RECT  17.448 7.619 18.6 8.531 ;
     RECT  17.352 8.531 18.6 9.397 ;
     RECT  17.352 9.397 18.336 11.365 ;
     RECT  2.712 12.083 3.696 14.293 ;
     RECT  11.832 13.139 13.104 13.715 ;
     RECT  11.544 13.715 13.104 14.821 ;
     RECT  3.72 14.723 4.8 17.075 ;
     RECT  11.544 14.821 12.912 15.011 ;
     RECT  13.104 15.491 13.2 16.645 ;
     RECT  17.256 16.019 18.48 16.259 ;
     RECT  13.944 16.115 15.12 16.595 ;
     RECT  17.16 16.259 18.48 16.787 ;
     RECT  16.968 16.787 18.48 17.605 ;
     RECT  3.576 17.075 4.8 18.181 ;
     RECT  21.816 17.603 22.8 18.851 ;
     RECT  16.968 17.605 18.192 17.989 ;
     RECT  16.968 18.131 18.192 18.275 ;
     RECT  3.768 18.181 4.8 18.419 ;
     RECT  3.768 18.419 5.1 19.379 ;
     RECT  6.264 18.563 7.632 20.003 ;
     RECT  21.816 18.851 23.088 19.331 ;
     RECT  16.536 19.235 16.584 20.389 ;
     RECT  21.72 19.331 23.088 20.195 ;
     RECT  3.576 19.379 5.1 22.547 ;
     RECT  8.904 19.475 9.936 21.683 ;
     RECT  11.448 19.909 12.768 20.581 ;
     RECT  6.264 20.003 7.68 20.533 ;
     RECT  15.648 20.003 15.9 20.341 ;
     RECT  21.72 20.195 22.248 20.293 ;
     RECT  13.512 20.341 14.64 20.485 ;
     RECT  14.664 20.341 15.9 21.541 ;
     RECT  6.36 20.533 7.68 21.155 ;
     RECT  11.976 20.627 13.104 21.107 ;
     RECT  21.612 20.675 22.248 21.973 ;
     RECT  11.832 21.107 13.104 22.069 ;
     RECT  7.632 21.155 7.68 21.541 ;
     RECT  16.968 21.493 18.192 21.683 ;
     RECT  8.904 21.683 10.368 21.731 ;
     RECT  16.968 21.683 18.24 22.259 ;
     RECT  22.536 21.973 24 22.213 ;
     RECT  11.976 22.069 13.104 22.501 ;
     RECT  16.968 22.259 18.336 22.787 ;
     RECT  14.28 22.403 15.552 22.835 ;
     RECT  11.976 22.501 13.056 22.643 ;
     RECT  2.712 22.547 5.1 22.789 ;
     RECT  10.812 22.643 11.808 22.739 ;
     RECT  11.976 22.643 13.104 23.411 ;
     RECT  10.812 22.739 11.952 23.411 ;
     RECT  16.92 22.787 18.336 23.267 ;
     RECT  2.712 22.789 4.272 23.555 ;
     RECT  14.28 22.835 15.792 22.883 ;
     RECT  19.896 23.123 21.3 23.411 ;
     RECT  21.612 23.123 23.088 23.411 ;
     RECT  2.712 23.555 2.856 23.941 ;
     RECT  2.76 23.941 2.856 24.517 ;
  END
END qfd_landh0d8_32_EW_28x26
END LIBRARY
